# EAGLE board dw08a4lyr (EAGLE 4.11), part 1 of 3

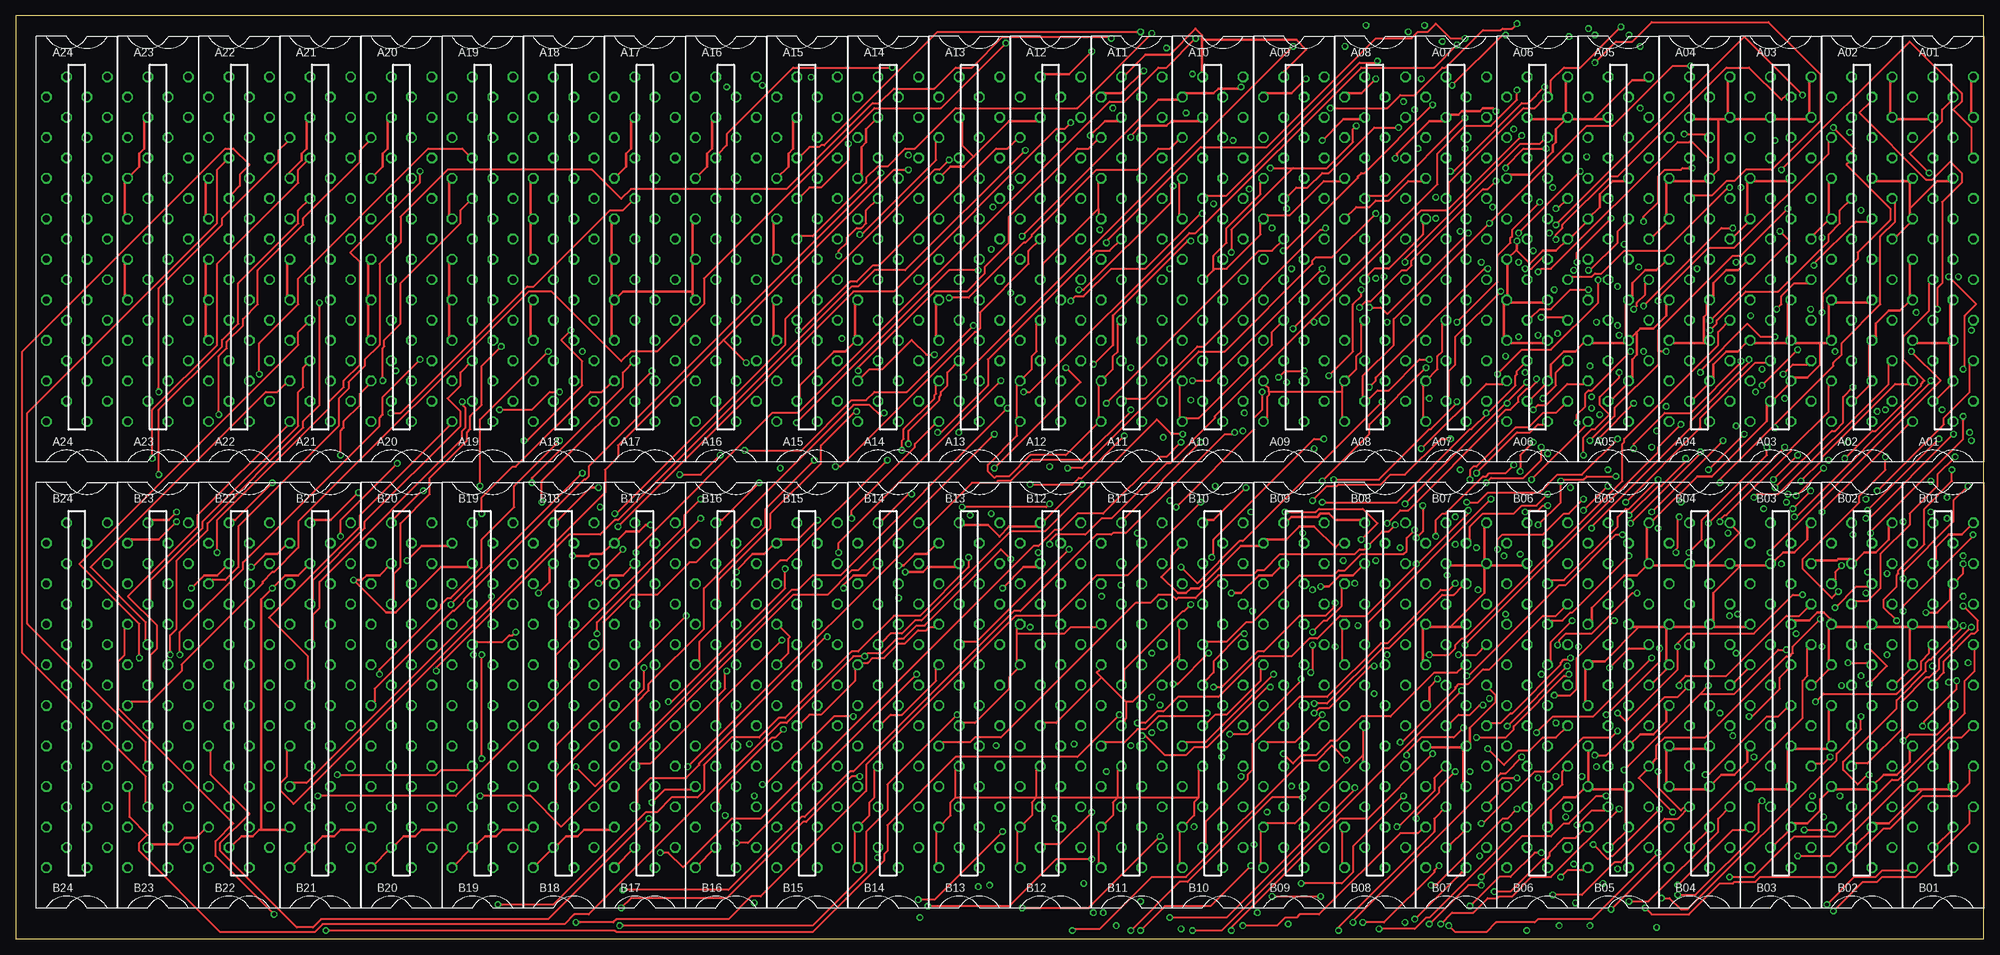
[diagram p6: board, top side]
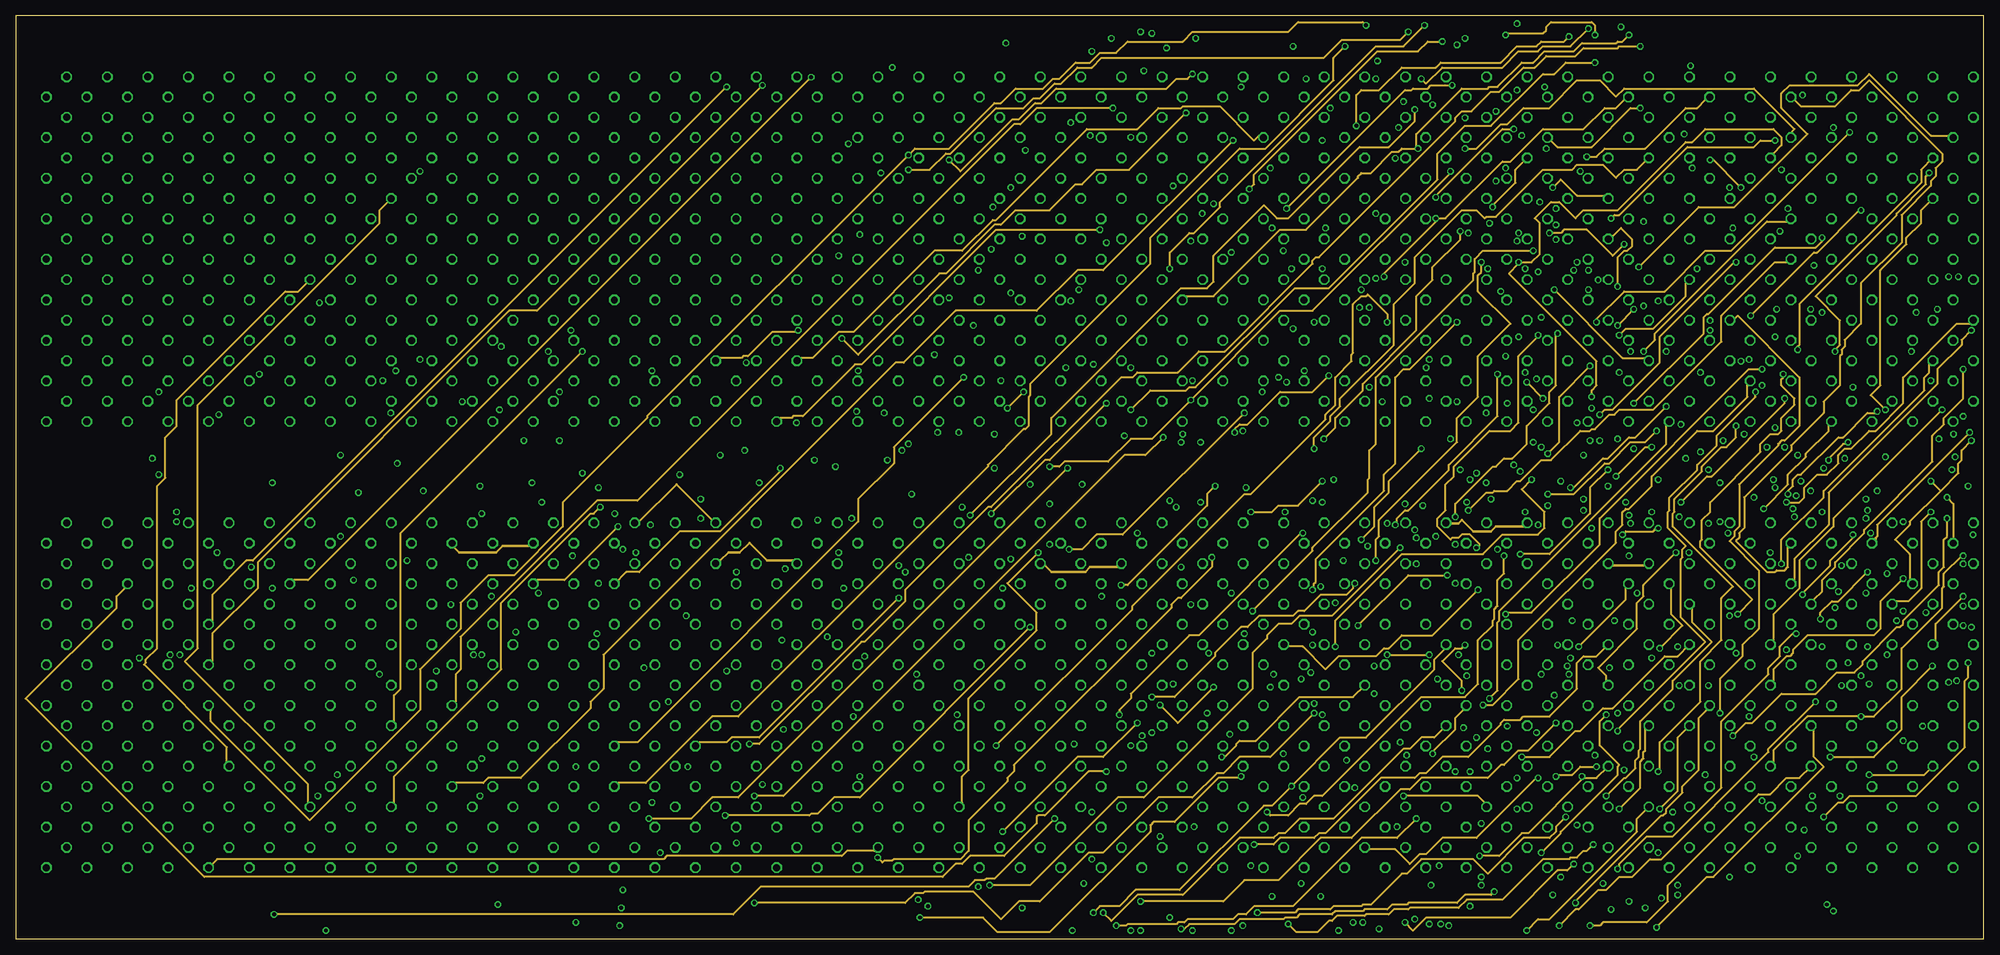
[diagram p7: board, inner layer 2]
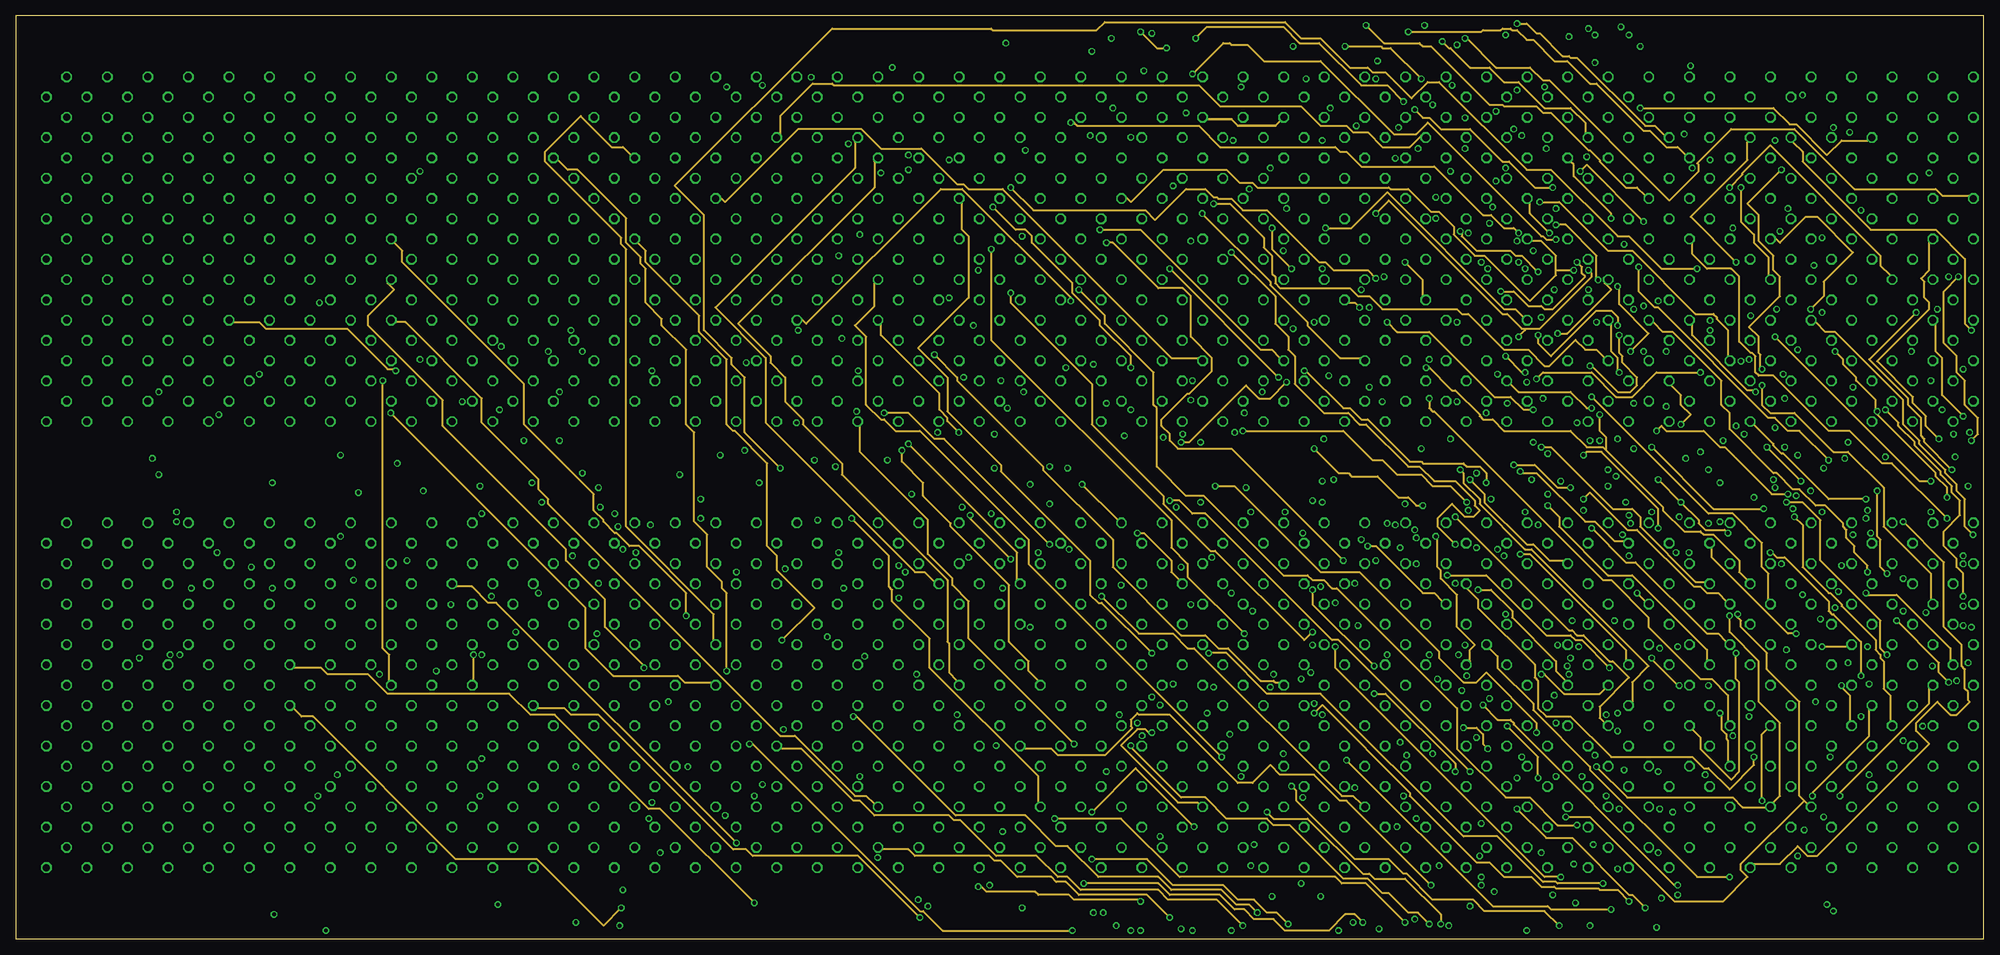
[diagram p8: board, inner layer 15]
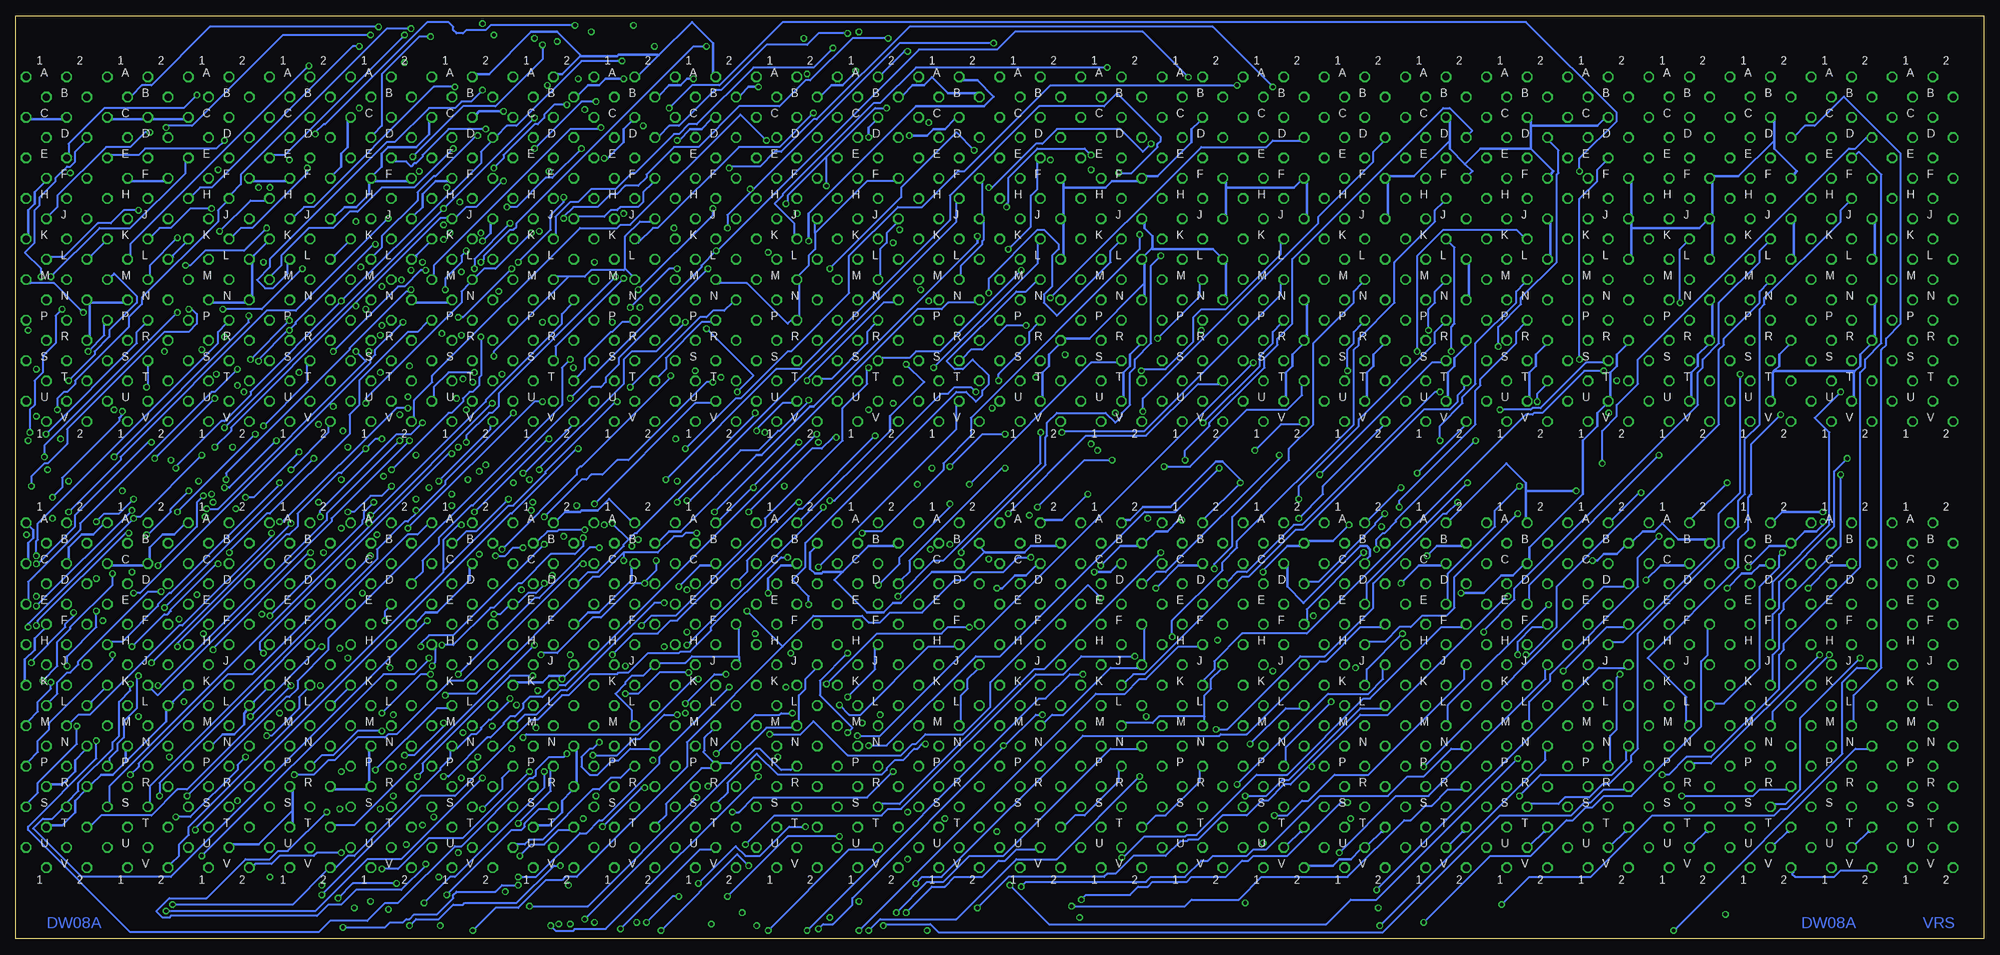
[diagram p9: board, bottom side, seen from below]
Size 307.98 x 144.46 mm. Coordinates in mm from the lower left corner, seen from the top.
Outline: 0,0 307.98,0 307.98,144.46 0,144.46 0,0
Copper layers (1*2*15*16): Top 0.035mm / dielectric 1.5mm / 2 0.035mm / dielectric 0.15mm / 15 0.035mm / dielectric 0.2mm / Bottom 0.035mm
Design rules "10mils": minimum track width 12mil, minimum drill 24mil, track to track 10mil, track to pad 10mil, pad to pad 10mil, via to via 10mil, smd to smd 10mil, copper to edge 25mil, drill to drill 10mil, minimum pad ring 10mil, minimum via ring 8mil, stop-mask expansion 0mil, vias tented up to drill 0mil, thermal gap 10mil
Net classes: 1 supply: width 0.381 mm

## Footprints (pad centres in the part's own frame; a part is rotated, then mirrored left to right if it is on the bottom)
H807 = drill 1.092 octagon: A1 4.763,28.575; A2 -1.587,28.575; B1 1.587,25.4; B2 -4.763,25.4; C1 4.763,22.225; C2 -1.587,22.225; D1 1.587,19.05; D2 -4.763,19.05; E1 4.763,15.875; E2 -1.587,15.875; F1 1.587,12.7; F2 -4.763,12.7; H1 4.763,9.525; H2 -1.587,9.525; J1 1.587,6.35; J2 -4.763,6.35; K1 4.763,3.175; K2 -1.587,3.175; L1 1.587,0; L2 -4.763,0; M1 4.763,-3.175; M2 -1.587,-3.175; N1 1.587,-6.35; N2 -4.763,-6.35; P1 4.763,-9.525; P2 -1.587,-9.525; R1 1.587,-12.7; R2 -4.763,-12.7; S1 4.763,-15.875; S2 -1.587,-15.875; T1 1.587,-19.05; T2 -4.763,-19.05; U1 4.763,-22.225; U2 -1.587,-22.225; V1 1.587,-25.4; V2 -4.763,-25.4

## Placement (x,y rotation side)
A01  M903  [H807]  301.62,106.36 0 top
A02  M903  [H807]  288.93,106.36 0 top
A03  M903  [H807]  276.23,106.36 0 top
A04  M903  [H807]  263.52,106.36 0 top
A05  M903  [H807]  250.82,106.36 0 top
A06  M907  [H807]  238.12,106.36 0 top
A07  M651  [H807]  225.43,106.36 0 top
A08  M651  [H807]  212.72,106.36 0 top
A09  M651  [H807]  200.03,106.36 0 top
A10  M651  [H807]  187.32,106.36 0 top
A11  M651  [H807]  174.62,106.36 0 top
A12  M651  [H807]  161.93,106.36 0 top
A13  W011  [H807]  149.22,106.36 0 top
A14  W011  [H807]  136.53,106.36 0 top
A15  W011  [H807]  123.83,106.36 0 top
A16  W011  [H807]  111.12,106.36 0 top
A17  W011  [H807]  98.42,106.36 0 top
A18  W011  [H807]  85.72,106.36 0 top
A19  W011  [H807]  73.03,106.36 0 top
A20  W011  [H807]  60.33,106.36 0 top
A21  W011  [H807]  47.62,106.36 0 top
A22  W011  [H807]  34.92,106.36 0 top
A23  W011  [H807]  22.23,106.36 0 top
A24  H807  [H807]  9.53,106.36 0 top
B01  M903  [H807]  301.62,36.51 0 top
B02  M903  [H807]  288.93,36.51 0 top
B03  M903  [H807]  276.23,36.51 0 top
B04  M903  [H807]  263.52,36.51 0 top
B05  M903  [H807]  250.82,36.51 0 top
B06  M101  [H807]  238.12,36.51 0 top
B07  M907  [H807]  225.43,36.51 0 top
B08  M651  [H807]  212.72,36.51 0 top
B09  M651  [H807]  200.03,36.51 0 top
B10  M651  [H807]  187.32,36.51 0 top
B11  M651  [H807]  174.62,36.51 0 top
B12  M651  [H807]  161.93,36.51 0 top
B13  M651  [H807]  149.22,36.51 0 top
B14  M651  [H807]  136.53,36.51 0 top
B15  M651  [H807]  123.83,36.51 0 top
B16  M517  [H807]  111.12,36.51 0 top
B17  M517  [H807]  98.42,36.51 0 top
B18  M517  [H807]  85.72,36.51 0 top
B19  M517  [H807]  73.03,36.51 0 top
B20  M517  [H807]  60.33,36.51 0 top
B21  M517  [H807]  47.62,36.51 0 top
B22  M517  [H807]  34.92,36.51 0 top
B23  M517  [H807]  22.23,36.51 0 top
B24  H807  [H807]  9.53,36.51 0 top

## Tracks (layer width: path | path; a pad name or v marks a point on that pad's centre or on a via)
-15V  (via drill 0.61)
  Top 0.381: v87.12,59.94 89.66,59.94 89.92,60.2 91.69,60.2 92.96,61.47 B17.B2 95.5,63.75 97.54,63.75 98.55,64.77 v99.31,64.77 | v25.15,65.28 22.35,62.48 18.03,62.48 B23.B2 | v61.21,59.18 63.5,61.47 67.56,61.47 B19.B2 | v36.83,58.17 37.08,58.17 39.12,60.2 40.89,60.2 42.16,61.47 B21.B2 | v191.77,133.35 191.52,133.1 188.21,133.1 187.45,132.33 183.13,132.33 A10.B2 181.86,131.32 178.82,131.32 v157.48,109.98 | v212.85,134.62 210.57,132.33 208.53,132.33 A08.B2 | v201.93,134.62 199.64,132.33 195.83,132.33 A09.B2 | v176.53,135.89 172.97,132.33 170.43,132.33 A11.B2 | v125.48,65.53 122.43,62.48 119.63,62.48 B15.B2 118.36,61.47 117.09,60.2 115.32,60.2 112.78,57.66 v112.78,57.4 | B08.B2 207.26,61.98 206.5,61.21 203.2,64.52 200.91,64.52 198.88,62.48 195.83,62.48 B09.B2 194.56,61.47 191.77,61.47 185.17,54.86 183.9,54.86 183.13,54.1 181.86,54.1 179.32,56.64 180.85,58.17 180.85,59.94 182.12,61.21 B10.B2 | v138.18,58.42 138.94,58.42 140.72,60.2 142.49,60.2 143.76,61.47 B13.B2
  2 0.381: B18.B2 80.26,61.47 76.2,61.47 75.18,60.45 69.34,60.45 68.58,61.21 B19.B2
  Bottom 0.381: v87.12,59.94 85.6,61.47 81.53,61.47 B18.B2 | v99.31,64.77 101.85,62.23 105.66,62.23 B16.B2 106.93,61.47 108.97,61.47 112.78,57.66 v112.78,57.4 | v25.15,65.28 25.15,64.77 26.16,63.75 27.94,63.75 29.46,62.23 B22.B2 30.73,61.47 33.53,61.47 v36.83,58.17 | B21.B2 43.43,62.48 47.75,62.48 50.29,65.02 51.56,63.75 53.34,63.75 54.86,62.23 B20.B2 56.13,61.47 57.4,60.2 59.44,60.2 60.45,59.18 v61.21,59.18 | A12.B2 157.73,132.33 162.05,132.33 164.59,134.87 165.86,133.6 167.64,133.6 169.16,132.08 A11.B2 | v191.77,133.35 193.29,133.35 194.56,132.08 A09.B2 | v212.85,134.62 215.65,134.62 216.66,133.6 218.44,133.6 219.96,132.08 A07.B2 | v201.93,134.62 202.95,134.62 203.96,133.6 205.74,133.6 207.26,132.08 A08.B2 | v176.53,135.89 176.53,135.64 178.56,133.6 180.34,133.6 181.86,132.08 A10.B2 | v125.48,65.53 125.98,65.53 127.76,63.75 129.54,63.75 131.06,62.23 B14.B2 132.33,61.47 135.13,61.47 v138.18,58.42 | 156.34,60.58 156.97,61.21 B12.B2 | 156.34,60.58 156.21,60.45 150.11,60.45 149.1,61.47 145.03,61.47 B13.B2 | 178.56,57.4 174.5,61.47 170.43,61.47 B11.B2 | 178.56,57.4 181.61,57.4 181.86,57.15 182.88,57.15 183.64,57.91 183.64,60.45 182.88,61.21 B10.B2 | 178.56,57.4 179.83,56.13 174.75,51.05 172.21,51.05 170.69,52.58 169.42,52.58 164.59,57.4 159.51,57.4 156.34,60.58 | v157.48,109.98 157.48,108.97 183.13,83.31 183.64,83.31 191.26,75.69 192.02,75.69 203.96,63.75 205.74,63.75 207.26,62.23 B08.B2
A06U1  (via drill 0.61)
  Top 0.305: v227.58,71.88 227.58,73.41 228.09,73.91 228.6,73.91 234.7,80.01 236.73,80.01 239.01,82.3 241.05,82.3 A06.U1 | A07.J2 220.22,112.01 220.22,110.24 214.88,104.9 212.6,104.9 211.58,103.89 A08.M2 | A07.F2 219.96,118.62 217.93,118.62 214.88,115.57 212.85,115.57 211.84,114.55 209.8,114.55 A08.J2 | 169.42,114.3 169.42,118.36 A11.F2 | 169.42,114.3 169.42,113.28 A11.J2 | 169.42,114.3 160.78,105.66 160.78,103.89 A12.M2 | A10.J2 182.12,113.28 182.12,118.36 A10.F2 | 187.45,104.65 186.44,103.63 A10.M2 | 187.45,104.65 187.71,104.9 189.48,104.9 194.82,110.24 194.82,112.01 A09.J2 195.83,113.28 199.39,113.28 204.72,118.62 207.26,118.62 A08.F2 | 187.45,104.65 187.45,106.93 189.48,108.97 189.48,111.25 194.82,116.59 194.82,118.36 A09.F2
  15 0.305: v227.58,71.88 229.87,69.6 229.87,68.33 236.47,61.72 237.49,61.72 240.03,59.18 242.32,59.18 B06.C1 | v236.22,88.65 235.71,88.65 v233.17,91.19
  Bottom 0.305: 212.6,104.9 212.6,109.98 210.31,112.27 208.53,112.27 A08.J2 | 212.6,104.9 211.58,103.89 A08.M2 | 221.49,103.63 218.95,103.63 217.93,104.65 212.85,104.65 212.6,104.9 | 221.49,103.63 223.27,103.63 A07.M2 | A12.F2 156.72,118.36 156.72,113.28 A12.J2 156.46,112.27 156.46,109.47 156.72,109.22 156.72,108.71 160.02,105.41 160.02,103.89 A12.M2 | A11.M2 172.72,103.89 172.72,107.95 171.7,108.97 171.7,110.49 170.18,112.01 A11.J2 | A09.M2 197.87,102.62 193.55,102.62 187.2,96.27 186.44,97.03 A10.P2 185.42,97.54 185.42,102.62 A10.M2 185.42,103.89 183.9,105.41 183.9,106.93 182.88,107.95 182.88,110.49 | 182.88,110.49 182.88,112.01 A10.J2 | 182.88,110.49 174.75,118.62 170.43,118.62 A11.F2 | A07.J2 219.96,113.03 215.9,113.03 214.88,114.05 213.87,114.05 213.36,114.55 210.57,114.55 209.8,115.32 209.8,116.84 208.28,118.36 A08.F2 | v236.22,88.65 240.28,88.65 242.57,86.36 242.57,84.84 A06.U1 | v233.17,91.19 233.17,91.95 221.49,103.63
A06V1  (via drill 0.61)
  Top 0.305: A12.P2 159.77,96.27 159.77,91.95 159,91.19 159,89.15 A12.T2 156.72,86.61 156.72,81.53 A12.V2 156.72,80.26 156.72,78.74 152.15,74.17 152.15,73.15 153.16,72.14 153.42,72.39 155.45,72.39 158.75,75.69 164.34,75.69 169.16,80.52 A11.V2 169.42,81.53 169.42,86.61 A11.T2 171.7,89.15 171.7,91.19 172.47,91.95 172.47,96.27 A11.P2 | A10.T2 182.12,86.61 182.12,81.53 A10.V2 183.13,81.53 185.17,81.53 196.6,92.96 196.6,95 A09.P2 | 196.09,85.6 196.09,86.11 195.58,86.61 A09.T2 | 196.09,85.6 196.09,85.09 195.83,84.84 195.83,81.53 A09.V2 | 207.52,85.6 207.52,86.61 A08.T2 209.8,89.15 209.8,91.19 210.57,91.95 210.57,96.27 A08.P2 | 207.52,85.6 207.52,81.53 A08.V2 | 207.52,85.6 196.09,85.6 | A07.V2 220.22,81.53 220.22,86.61 A07.T2 222.5,89.15 222.5,91.19 223.27,91.95 223.27,96.27 A07.P2 | v228.6,72.9 234.95,79.25 236.98,79.25 238.25,80.52 239.01,80.52 A06.V1
  Bottom 0.305: A10.T2 181.86,87.63 180.34,87.63 174.75,93.22 174.75,95 173.48,96.27 A11.P2 | A09.P2 199.14,96.52 200.66,96.52 206.25,90.93 206.25,89.15 207.52,87.88 A08.T2 | v228.6,72.9 228.35,72.9 220.98,80.26 A07.V2 | A08.P2 211.84,96.52 213.11,96.52 214.63,95 214.88,95 218.95,90.93 218.95,89.15 220.22,87.88 A07.T2
B07U1
  Top 0.305: B09.V2 194.82,11.68 194.82,16.76 B09.T2 195.83,18.03 200.15,18.03 210.82,28.7 | 210.82,28.7 210.82,32.77 B08.M2 | 210.82,28.7 210.82,27.69 B08.P2 | B13.F2 143.76,48.77 143,48.77 142.49,48.26 141.22,48.26 139.19,46.23 138.18,46.23 135.89,43.94 134.11,43.94 133.35,43.18 132.33,43.18 B14.J2 131.32,42.16 131.32,40.39 125.98,35.05 124.21,35.05 122.94,33.78 B15.M2 | B13.J2 144.02,42.16 144.02,40.39 138.68,35.05 136.91,35.05 135.64,33.78 B14.M2 | B15.F2 119.63,48.77 121.16,47.24 120.9,46.99 120.9,44.7 B15.J2 | B13.M2 148.34,33.78 150.11,33.78 155.45,39.12 155.45,40.89 156.72,42.16 B12.J2 156.72,43.43 156.72,47.75 | 156.72,47.75 156.72,48.51 B12.F2 | 156.72,47.75 164.08,47.75 165.1,48.77 169.16,48.77 B11.F2 | B08.V2 207.52,11.68 207.52,16.76 B08.T2 | 173.74,37.08 173.74,34.54 173.48,34.29 173.48,34.04 B11.M2 | 169.93,40.89 169.16,41.66 169.67,42.16 B11.J2 | 173.74,37.08 169.93,40.89 | B08.J2 207.52,43.43 207.52,48.51 B08.F2 | 182.12,44.45 182.12,43.43 B10.J2 | 182.12,44.45 182.12,48.51 B10.F2 | B09.J2 194.82,42.16 194.82,40.39 189.48,35.05 187.71,35.05 186.44,33.78 B10.M2 | 173.74,37.08 174.75,37.08 182.12,44.45 | 169.93,40.89 162.81,33.78 161.04,33.78 B12.M2
  Bottom 0.305: B07.U1 229.62,14.73 228.35,14.73 227.58,15.49 225.55,15.49 217.68,23.37 216.66,23.37 214.88,25.15 213.36,25.15 211.84,26.67 B08.P2 | B14.F2 131.32,48.51 131.32,43.43 B14.J2 132.33,42.42 136.65,42.42 144.02,35.05 145.8,35.05 147.07,33.78 B13.M2 | 121.92,34.8 121.92,38.1 120.9,39.12 120.9,40.64 119.38,42.16 B15.J2 | 121.92,34.8 121.92,34.04 B15.M2 | 121.92,34.8 129.03,34.8 130.05,33.78 134.37,33.78 B14.M2 | B12.M2 160.02,34.04 160.02,38.1 159,39.12 159,40.64 157.48,42.16 B12.J2 | B09.P2 198.88,27.69 200.41,29.21 200.15,29.46 200.15,31.5 198.88,32.77 B09.M2 | B09.P2 199.14,26.67 200.66,26.67 206.25,21.08 206.25,19.3 207.52,18.03 B08.T2 | 194.82,44.2 194.82,48.51 B09.F2 | 194.82,44.2 194.82,43.43 B09.J2 | B10.J2 182.88,42.16 184.4,40.64 184.4,39.12 185.42,38.1 185.42,34.04 B10.M2 186.44,33.02 190.5,33.02 196.09,27.43 197.87,27.43 B09.P2 | 194.82,44.2 202.18,44.2 203.2,43.18 207.26,43.18 B08.J2 208.53,42.42 209.8,41.15 211.58,41.15 212.6,40.13 212.6,39.88 214.12,38.35 211.58,35.81 211.58,34.04 B08.M2
B07V1  (via drill 0.61)
  Top 0.305: B14.V2 131.32,11.68 131.32,16.76 B14.T2 133.6,19.3 133.6,21.34 134.37,22.1 134.37,26.42 B14.P2 | B13.V2 144.02,11.68 144.02,16.76 B13.T2 146.3,19.3 146.3,21.34 147.07,22.1 | 147.07,22.1 147.07,26.42 B13.P2 | B12.V2 156.72,11.68 156.72,16.76 B12.T2 159,19.3 159,21.34 159.77,22.1 | 159.77,22.1 159.77,26.42 B12.P2 | 147.07,22.1 159.77,22.1 | B11.V2 169.42,11.68 169.42,16.76 B11.T2 171.7,19.3 171.7,21.34 172.47,22.1 | 172.47,22.1 172.47,26.42 B11.P2 | B10.V2 182.12,11.68 182.12,16.76 B10.T2 184.4,19.3 184.4,21.34 185.17,22.1 | 185.17,22.1 185.17,26.42 B10.P2 | v218.95,3.05 226.31,10.41 226.57,10.41 B07.V1 | 172.47,22.1 185.17,22.1 | 159.77,22.1 172.47,22.1
  Bottom 0.305: B15.P2 122.68,26.42 122.68,24.64 128.02,19.3 129.54,19.3 131.06,17.78 B14.T2 | B14.P2 135.38,26.42 135.38,24.64 140.72,19.3 142.24,19.3 143.76,17.78 B13.T2 | v218.95,3.05 192.28,29.72 191.52,29.72 188.21,26.42 186.69,26.42 186.44,26.67 B10.P2
GND  (via drill 0.61)
  Top 0.381: 264.16,93.22 264.41,93.22 A04.R1 | 264.16,93.22 259.33,93.22 A04.R2 | 264.16,93.22 264.16,97.28 264.67,97.79 264.67,99.31 A04.N1 265.68,100.58 265.68,102.62 267.72,104.65 269.49,104.65 270.76,105.92 A03.L2 | A04.K1 268.99,109.98 271.02,112.01 A03.J2 271.02,113.28 271.02,118.36 A03.F2 272.03,118.62 277.11,118.62 A03.F1 | A03.K1 281.43,110.24 283.46,112.27 A02.J2 283.72,113.28 283.72,118.36 A02.F2 | A02.K1 294.39,109.98 296.42,112.01 A01.J2 296.42,113.28 296.42,114.3 | 296.42,114.3 296.42,118.36 A01.F2 296.16,118.62 291.08,118.62 A02.F1 | 296.42,114.3 300.74,118.62 302.51,118.62 A01.F1 | A02.U2 288.04,84.58 290.07,86.61 A02.T1 290.07,87.88 290.07,92.96 A02.R1 291.08,94.23 291.08,96.27 293.12,98.3 294.89,98.3 296.16,99.57 A01.N2 296.42,100.58 296.42,105.66 A01.L2 | A01.U2 300.74,84.58 302.77,86.61 A01.T1 302.77,87.88 302.77,92.96 A01.R1 | A01.R2 297.43,93.22 302.51,93.22 A01.R1 | A01.N1 302.77,99.31 302.77,94.23 A01.R1 | A04.U2 262.64,84.58 264.67,86.61 A04.T1 265.68,87.88 265.68,89.92 267.72,91.95 269.49,91.95 270.76,93.22 A03.R2 272.03,93.22 277.11,93.22 A03.R1 | 282.45,93.22 278.38,93.22 A03.R1 | 282.45,93.22 283.46,93.22 A02.R2 283.72,94.23 283.72,99.31 A02.N2 284.73,99.57 289.81,99.57 A02.N1 | 282.45,93.22 282.45,89.92 280.42,87.88 278.38,87.88 A03.T1 277.37,86.61 275.34,84.58 A03.U2 274.07,83.57 274.07,81.03 265.43,72.39 263.14,72.39 256.29,65.53 B05.A1 255.27,64.52 255.27,59.44 B05.C1 | A03.N1 277.37,99.31 277.37,94.23 A03.R1 | 266.45,128.27 267.72,128.27 A04.C1 | 266.45,128.27 262.64,128.27 A04.C2 | A04.C1 268.99,128.27 274.07,128.27 A03.C2 275.34,128.27 280.42,128.27 A03.C1 280.67,129.29 280.67,134.37 A03.A1
  Top 0.381: A04.A1 267.97,134.37 267.97,129.29 A04.C1 | A01.C2 299.47,128.27 294.39,128.27 A02.C1 293.37,129.29 293.37,134.37 A02.A1 | A01.A1 306.07,134.37 306.07,129.29 A01.C1 | v231.65,129.54 231.14,130.05 229.62,130.05 229.11,129.54 226.31,129.54 225.81,129.03 224.54,129.03 A07.C2 223.27,128.02 221.23,128.02 216.15,122.94 216.15,122.43 v215.9,122.17 | A06.F2 233.93,119.63 236.98,119.63 240.54,123.19 240.54,124.21 241.05,124.71 241.05,126.75 A06.C1 | 246.89,128.27 243.59,128.27 A06.C1 | 246.89,128.27 248.67,128.27 A05.C2 | A06.A1 242.57,134.37 242.57,129.29 A06.C1 | 246.89,128.27 252.98,134.37 255.02,134.37 A05.A1 | A06.C2 237.24,128.27 242.32,128.27 A06.C1 | A05.U2 249.94,84.58 251.97,86.61 A05.T1 252.98,87.88 252.98,90.68 253.75,91.44 253.75,94.74 253.62,94.87 | A06.U2 237.24,84.58 239.27,86.61 A06.T1 240.28,87.88 240.28,89.92 242.32,91.95 244.09,91.95 245.36,93.22 A05.R2 246.63,93.22 251.71,93.22 A05.R1 | A05.R1 251.97,94.23 251.97,99.31 A05.N1 252.98,100.58 252.98,102.62 255.02,104.65 256.79,104.65 258.06,105.92 A04.L2 | 253.62,94.87 254.25,95.5 256.29,95.5 258.32,97.54 258.32,99.31 A04.N2 | A05.R1 253.62,94.87 | A06.R1 239.01,93.22 233.93,93.22 A06.R2 232.92,94.23 232.92,99.31 A06.N2 | A06.N1 239.01,99.57 233.93,99.57 A06.N2 | A06.N2 233.43,100.58 233.43,105.66 A06.L2 234.82,107.82 | v234.95,109.22 234.95,107.95 234.82,107.82 | A05.F1 251.71,118.62 249.94,118.62 247.9,116.59 247.9,114.55 A05.J2 245.62,112.01 243.59,109.98 A06.K1 241.05,107.7 239.01,107.7 236.98,105.66 234.82,107.82 | A05.K1 256.29,109.98 258.32,112.01 A04.J2 258.32,113.28 258.32,118.36 A04.F2 259.33,118.62 264.41,118.62 A04.F1 266.45,120.4 266.45,128.27
  Top 0.381: B07.U2 224.54,14.73 226.57,16.76 B07.T1 | B07.R1 226.57,24.38 226.57,29.46 B07.N1 | B07.N2 221.23,29.97 226.31,29.97 B07.N1 | B07.C2 224.54,58.42 229.62,58.42 B07.C1 | B06.C2 235.97,58.42 230.89,58.42 B07.C1 | B07.A1 229.87,64.52 229.87,59.44 B07.C1 | v222.5,40.64 221.23,39.37 221.23,37.08 B07.L2 | v190.25,54.1 191.77,54.1 194.56,56.9 196.6,56.9 B09.C2 | 224.54,48.77 221.23,48.77 B07.F2 220.22,48.51 220.22,43.43 B07.J2 | 224.54,48.77 226.31,48.77 B07.F1 | v204.22,55.12 205.49,55.12 207.26,56.9 209.3,56.9 B08.C2 | 224.54,48.77 229.87,54.1 229.87,58.17 B07.C1 | B07.N1 227.58,30.73 227.58,33.02 231.65,37.08 231.65,38.1 230.63,39.12 B07.K1 | B05.K1 256.29,40.13 258.32,42.16 B04.J2 258.32,43.43 258.32,48.51 B04.F2 | B05.L2 245.62,37.08 245.62,42.16 B05.J2 246.63,43.43 248.67,43.43 254,48.77 | 254,48.77 258.06,48.77 B04.F2 | 254,48.77 252.98,48.77 B05.F1 | B04.F1 264.41,48.77 259.33,48.77 B04.F2 | B03.F2 270.76,48.77 265.68,48.77 B04.F1 | B01.C2 300.48,59.44 300.48,61.21 302.51,63.25 304.55,63.25 B01.A1 | B03.C1 281.69,59.18 284.99,59.18 285.24,59.44 287.02,59.44 B02.C2 288.04,59.18 289.31,60.45 291.08,60.45 293.12,62.48 293.12,64.52 B02.A1 | B05.F2 246.63,49.78 246.63,51.82 251.71,56.9 253.75,56.9 B05.C1 | B05.C1 256.29,58.42 261.37,58.42 B04.C2 262.64,58.42 264.67,58.42 | 264.67,58.42 267.72,58.42 B04.C1 268.99,58.42 270,58.42 | 270,58.42 274.07,58.42 B03.C2 275.34,59.18 276.61,60.45 278.38,60.45 280.42,62.48 280.42,64.52 B03.A1 | 264.67,58.42 269.75,63.5 268.73,64.52 B04.A1 | 270,58.42 265.68,54.1 265.68,49.78 B04.F1 | B03.K1 281.69,40.13 283.72,42.16 B02.J2 283.72,43.43 283.72,48.51 B02.F2
  Top 0.381: B04.K1 268.99,40.13 271.02,42.16 B03.J2 | B03.R2 272.03,23.37 277.11,23.37 B03.R1 277.37,24.38 277.37,29.46 B03.N1 278.38,29.72 283.46,29.72 B02.N2 283.72,30.73 283.72,35.81 B02.L2 | B03.F1 278.38,49.78 280.67,49.78 281.94,51.05 282.96,51.05 283.97,50.04 283.72,49.78 B02.F2 | B02.F2 284.73,48.77 289.81,48.77 B02.F1 291.08,48.77 296.16,48.77 B01.F2 | B02.K1 294.39,40.13 296.42,42.16 B01.J2 296.42,43.43 296.42,48.51 B01.F2 | B01.F1 302.51,48.77 297.43,48.77 B01.F2 | B01.U2 300.74,14.73 302.77,16.76 B01.T1 | B02.U2 288.04,14.73 290.07,16.76 B02.T1 291.08,18.03 293.12,18.03 298.45,23.37 | 298.45,23.37 297.43,23.37 B01.R2 | 298.45,23.37 302.51,23.37 B01.R1 302.77,24.38 302.77,29.46 B01.N1 | B03.U2 275.34,14.73 277.37,16.76 B03.T1 278.38,18.03 280.42,18.03 282.45,20.07 282.45,21.84 283.72,23.11 B02.R2 284.73,23.37 289.81,23.37 B02.R1 292.35,25.65 294.39,25.65 296.42,27.69 296.42,29.46 B01.N2 | B04.U2 262.64,14.73 264.67,16.76 B04.T1 | B03.N2 271.02,29.46 271.02,27.69 268.99,25.65 266.95,25.65 B04.R1 264.41,23.37 259.33,23.37 B04.R2 258.32,24.38 258.32,29.46 B04.N2 259.33,29.72 264.41,29.72 B04.N1 | B06.T1 240.28,18.03 240.28,20.07 242.32,22.1 244.09,22.1 245.36,23.37 B05.R2 | B05.N2 246.13,29.46 246.13,24.38 B05.R2 | B05.U2 249.94,14.73 251.97,16.76 B05.T1 251.97,18.03 251.97,23.11 B05.R1 251.71,23.37 246.63,23.37 B05.R2 | B04.L2 258.32,35.81 258.32,34.04 256.29,32 254.25,32 B05.N1 | B16.V2 B16.U2 | B17.U2 B17.V2 | B18.V2 B18.U2 84.84,14.73 86.11,16 87.88,16 88.9,17.02 92.96,17.02 B17.T2 | B19.V2 B19.U2 72.14,14.73 73.41,16 75.18,16 76.2,17.02 80.26,17.02 B18.T2
  Top 0.381: B20.V2 B20.U2 59.44,14.73 60.71,16 62.48,16 63.5,17.02 67.56,17.02 B19.T2 | B21.V2 B21.U2 46.74,14.73 48.01,16 49.78,16 50.8,17.02 54.86,17.02 B20.T2 | B23.U2 21.34,14.73 25.4,14.73 26.42,15.75 28.19,15.75 29.46,17.02 B22.T2 | 38.35,17.02 38.1,17.02 37.08,16 35.31,16 34.04,14.73 B22.U2 | 38.35,17.02 42.16,17.02 B21.T2 | v129.54,54.86 129.54,55.37 131.06,56.9 133.1,56.9 B14.C2 | v139.19,57.4 141.99,57.4 142.75,58.17 147.07,58.17 B13.C2 | v154.43,54.86 157.73,58.17 159.77,58.17 B12.C2 | v91.19,55.63 91.69,55.63 92.96,56.9 95,56.9 B17.C2 | v27.43,54.86 29.46,56.9 31.5,56.9 B22.C2 | B20.C2 56.9,56.9 54.86,56.9 54.1,56.13 v52.83,56.13 57.91,51.05 59.44,51.05 66.55,58.17 70.87,58.17 B19.C2 | B21.C2 44.2,56.9 42.16,56.9 v40.13,54.86 38.35,53.09 38.35,17.02 | v81.79,54.1 83.57,55.88 83.57,58.17 B18.C2 | v204.47,124.97 207.77,128.27 210.57,128.27 A08.C2 | A14.F2 132.33,119.63 132.33,123.95 133.1,124.71 133.1,126.75 A14.C2 | 149.86,122.43 148.08,124.21 148.08,128.02 A13.C2 | 149.86,122.43 148.34,120.9 146.3,120.9 A13.F2 | 149.86,122.43 155.45,128.02 159.77,128.02 A12.C2 | v168.15,125.73 170.43,128.02 172.47,128.02 A11.C2 | v174.5,125.48 174.5,125.73 176.02,127.25 180.09,127.25 180.85,128.02 185.17,128.02 A10.C2 | A13.R2 144.02,94.23 144.02,99.31 A13.N2 | A15.U2 122.68,84.84 122.68,86.61 128.02,91.95 129.79,91.95 131.06,93.22 A14.R2 131.32,94.23 131.32,99.31 A14.N2 | A15.R2 118.62,94.23 118.62,99.31 A15.N2 | A15.J2 118.62,112.01 118.62,106.93 A15.L2 | A15.C2 121.67,128.02 121.67,123.7 120.9,122.94 120.9,120.9 A15.F2 | 105.92,101.35 105.92,100.58 A16.N2 | 105.92,101.35 105.92,105.66 A16.L2 105.92,106.93 105.92,112.01 A16.J2
  Top 0.381: A16.C2 108.97,128.02 108.97,123.7 108.2,122.94 108.2,120.9 A16.F2 | A17.R2 93.22,94.23 93.22,99.31 A17.N2 | A17.N2 93.22,100.58 93.22,105.66 A17.L2 93.22,106.93 93.22,112.01 A17.J2 | A17.C2 96.27,128.02 96.27,123.7 95.5,122.94 95.5,120.9 A17.F2 | A19.R2 67.82,94.23 67.82,99.31 A19.N2 67.82,100.58 67.82,105.66 A19.L2 | A19.F2 67.82,118.36 67.82,113.28 A19.J2 | A18.R2 80.52,94.23 80.52,99.31 A18.N2 | A18.L2 80.52,106.93 80.52,112.01 A18.J2 80.52,113.28 80.52,118.36 A18.F2 | A20.R2 55.12,94.23 55.12,99.31 A20.N2 55.12,100.58 55.12,105.66 A20.L2 | A20.C2 58.17,128.02 58.17,123.7 57.4,122.94 57.4,120.9 A20.F2 | A21.L2 42.42,105.66 42.42,100.58 A21.N2 | A21.C2 45.47,128.02 45.47,123.7 44.7,122.94 44.7,121.92 42.42,119.63 A21.F2 | A23.L2 17.02,105.66 17.02,100.58 A23.N2 | A23.J2 17.02,113.28 17.02,118.36 A23.F2 19.3,120.9 19.3,122.94 20.07,123.7 20.07,128.02 A23.C2 | A22.R2 29.72,94.23 29.72,99.31 A22.N2 29.72,100.58 29.72,105.66 A22.L2 | A22.F2 29.72,118.36 29.72,113.28 A22.J2 | 105.92,101.35 95,101.35 A17.N2
  2 0.381: B05.C2 249.94,58.42 255.02,58.42 B05.C1 | B11.C2 172.47,58.17 168.15,58.17 167.39,57.4 162.05,57.4 161.04,58.42 B12.C2 | B15.C2 121.67,59.18 117.6,59.18 114.81,61.98 113.28,60.45 111.51,60.45 110.24,59.18 B16.C2
  15 0.381: A10.C2 186.44,128.27 190.25,128.27 191.26,127.25 197.1,127.25 A09.C2
  Bottom 0.381: A03.N1 277.11,99.57 272.03,99.57 A03.N2 271.02,100.58 271.02,105.66 A03.L2 270.76,106.68 270.76,106.93 268.73,108.97 A04.K1 | A02.L2 283.46,106.68 283.46,106.93 281.43,108.97 A03.K1 | A02.F1 289.81,118.62 284.73,118.62 A02.F2 | A01.L2 296.16,106.68 296.16,106.93 294.13,108.97 A02.K1 | A01.K1 306.07,110.24 306.07,114.05 305.05,115.06 305.05,116.84 303.53,118.36 A01.F1 | A01.R2 296.42,94.23 296.42,99.31 A01.N2 296.16,99.57 291.08,99.57 A02.N1 | A03.C1 281.69,128.27 286.77,128.27 A02.C2 288.04,128.27 293.12,128.27 A02.C1 | A01.C1 305.82,128.27 300.74,128.27 A01.C2 | v231.65,129.54 235.46,129.54 235.97,129.03 A06.C2 | A05.N2 245.36,99.57 240.28,99.57 A06.N1 | v234.95,109.22 233.68,110.49 233.68,112.01 A06.J2 | A05.F2 246.63,118.62 251.71,118.62 A05.F1 | A05.L2 245.36,106.68 245.36,106.93 243.33,108.97 A06.K1 | A06.F1 240.28,118.62 242.32,118.62 244.35,116.59 244.35,114.55 245.62,113.28 A05.J2 | A04.L2 258.06,106.68 258.06,106.93 256.03,108.97 A05.K1 | A05.C1 256.03,128.02 256.03,123.95 257.05,122.94 257.05,120.9 258.32,119.63 A04.F2 | A05.F1 252.73,118.36 252.73,116.59 254.76,114.55 256.54,114.55 258.06,113.03 A04.J2 | A06.C1 243.33,128.02 243.33,125.98 245.36,123.95 249.68,123.95 250.7,122.94 250.7,120.9 251.97,119.63 A05.F1 | A03.F2 270.76,118.62 265.68,118.62 A04.F1 | B07.N2 220.22,29.46 220.22,24.38 B07.R2 220.98,23.11 222.5,21.59 222.5,19.81 224.54,17.78 226.31,17.78 B07.T1 | 222.12,41.02 220.98,42.16 B07.J2 | 222.12,41.02 v222.5,40.64 | B07.K1 229.62,40.13 225.55,40.13 224.54,41.15 222.25,41.15 222.12,41.02 | v190.25,54.1 190.25,56.39 188.21,58.42 186.44,58.42 B10.C2
  Bottom 0.381: B08.C2 211.58,58.17 211.58,56.13 216.66,51.05 218.44,51.05 219.96,49.53 B07.F2 | v204.22,55.12 200.91,58.42 199.14,58.42 B09.C2 | B04.L2 258.06,36.83 258.06,37.08 256.03,39.12 B05.K1 | B01.C1 306.07,59.44 306.07,61.98 305.31,62.74 305.31,64.01 B01.A1 | B02.C1 293.12,58.42 288.04,58.42 B02.C2 287.02,59.44 287.02,61.21 284.99,63.25 283.21,63.25 281.69,64.77 B03.A1 | B01.C2 299.72,59.44 299.72,61.21 297.69,63.25 295.91,63.25 294.39,64.77 B02.A1 | B03.K1 281.43,39.12 283.46,37.08 283.46,36.83 B02.L2 284.48,35.81 284.48,34.04 290.83,27.69 | B04.K1 268.73,39.12 270.76,37.08 270.76,36.83 B03.L2 271.78,35.81 272.29,35.31 272.29,33.53 273.81,32 275.59,32 277.11,30.48 B03.N1 | B01.L2 296.16,36.83 296.16,37.08 294.13,39.12 B02.K1 | B01.K1 306.58,40.39 306.58,43.69 305.05,45.21 305.05,46.99 303.53,48.51 B01.F1 | 290.83,27.69 290.83,29.46 B02.N1 | 290.83,27.69 292.86,25.65 294.64,25.65 296.16,24.13 B01.R2 297.18,23.11 298.7,21.59 298.7,19.81 300.74,17.78 302.51,17.78 B01.T1 | B01.R1 302.51,24.13 300.74,24.13 298.7,26.16 298.7,27.94 297.18,29.46 B01.N2 | 264.67,20.07 264.67,18.03 B04.T1 | 264.67,20.07 264.67,23.11 B04.R1 | B05.N1 252.73,29.46 252.73,24.38 B05.R1 252.98,23.37 258.06,23.37 B04.R2 | 264.67,20.07 270,14.73 274.07,14.73 B03.U2 | B06.C2 236.98,58.17 236.98,56.13 242.06,51.05 243.84,51.05 245.36,49.53 B05.F2 | B16.T2 106.68,16.76 106.93,16.76 108.97,14.73 B16.U2 | B17.T2 93.98,16.76 94.23,16.76 96.27,14.73 B17.U2 97.54,13.97 99.06,12.45 100.84,12.45 101.85,11.43 105.66,11.43 B16.V2 | B18.T2 81.28,16.76 81.53,16.76 83.57,14.73 B18.U2 | B19.T2 68.58,16.76 68.83,16.76 70.87,14.73 B19.U2
  Bottom 0.381: B20.T2 55.88,16.76 56.13,16.76 58.17,14.73 B20.U2 | B21.T2 43.18,16.76 43.43,16.76 45.47,14.73 B21.U2 | B23.T2 17.78,16.76 18.03,16.76 20.07,14.73 B23.U2 | B22.T2 30.48,16.76 30.73,16.76 32.77,14.73 B22.U2 | v129.54,54.86 125.98,58.42 122.94,58.42 B15.C2 | v139.19,57.4 136.65,57.4 135.64,58.42 B14.C2 | v154.43,54.86 153.67,54.86 151.64,56.9 149.86,56.9 148.34,58.42 B13.C2 | v91.19,55.63 88.39,58.42 84.84,58.42 B18.C2 | B16.C2 108.97,58.17 108.97,55.12 106.43,52.58 97.54,61.47 96.52,61.47 96.01,60.96 96.01,59.94 96.52,59.44 B17.C2 | v27.43,54.86 23.88,58.42 21.34,58.42 B23.C2 | v52.83,56.13 50.55,58.42 46.74,58.42 B21.C2 | v40.13,54.86 37.85,57.15 36.32,57.15 35.05,58.42 34.04,58.42 B22.C2 | v81.79,54.1 78.23,54.1 75.44,56.9 73.66,56.9 72.14,58.42 B19.C2 71.12,59.44 71.12,61.21 62.74,69.6 62.74,77.98 60.45,80.26 60.45,82.3 59.18,83.57 A20.U2 58.42,84.84 58.42,88.65 57.4,89.66 57.4,91.44 55.88,92.96 A20.R2 | v204.47,124.97 204.22,124.97 202.44,126.75 200.66,126.75 199.14,128.27 A09.C2 | A13.L2 144.02,106.93 144.02,112.01 A13.J2 144.02,113.28 144.02,117.6 | 144.02,117.6 144.02,118.36 A13.F2 | v168.15,125.73 165.35,125.73 164.34,126.75 162.56,126.75 161.04,128.27 A12.C2 | 144.02,117.6 137.41,117.6 136.4,118.62 132.33,118.62 A14.F2 131.06,119.38 129.29,119.38 123.95,124.71 123.95,126.75 122.68,128.02 A15.C2 | v174.5,125.48 174.5,127 173.48,128.02 A11.C2 | A13.U2 147.32,84.84 147.32,88.65 146.3,89.66 146.3,91.44 144.78,92.96 A13.R2 143.76,93.98 139.95,93.98 131.32,102.62 | 131.32,102.62 131.32,100.58 A14.N2 | 131.32,102.62 131.32,105.66 A14.L2 131.32,106.93 130.18,108.08
  Bottom 0.381: A14.U2 134.62,84.84 134.62,88.65 133.6,89.66 133.6,91.44 132.08,92.96 A14.R2 | 130.18,108.08 130.05,108.2 130.05,109.98 131.32,111.25 131.32,112.01 A14.J2 | A15.N2 118.62,100.58 118.62,105.66 A15.L2 120.65,107.95 130.05,107.95 130.18,108.08 | 118.62,117.6 118.62,113.28 A15.J2 | 118.62,117.6 118.62,118.36 A15.F2 | A16.N2 105.92,99.31 105.92,94.23 A16.R2 106.68,92.96 108.2,91.44 108.2,89.66 109.22,88.65 109.22,84.84 A16.U2 | A16.J2 105.92,113.28 105.92,118.36 A16.F2 106.93,118.62 107.95,117.6 118.62,117.6 | A17.U2 96.52,84.84 96.52,88.65 95.5,89.66 95.5,91.44 93.98,92.96 A17.R2 | A17.J2 93.22,113.28 93.22,118.36 A17.F2 92.96,119.38 89.15,119.38 83.57,124.97 | A19.U2 71.12,84.84 71.12,88.65 70.1,89.66 70.1,91.44 68.58,92.96 A19.R2 | A19.J2 67.82,112.01 67.82,106.93 A19.L2 | 70.87,123.7 70.87,127.25 | 70.87,127.25 70.87,128.02 A19.C2 | 70.87,123.7 67.31,120.14 67.82,119.63 A19.F2 | A18.L2 80.52,105.66 80.52,100.58 A18.N2 | A18.U2 83.82,84.84 83.82,88.65 82.8,89.66 82.8,90.93 80.77,92.96 A18.R2 | 83.57,124.97 83.57,123.7 81.15,121.28 | 83.57,124.97 83.57,128.02 A18.C2 | 81.15,121.28 80.01,120.14 80.52,119.63 A18.F2 | 70.87,123.7 78.74,123.7 81.15,121.28 | 55.12,111.25 55.12,106.93 A20.L2 | 55.12,111.25 55.12,112.01 A20.J2 55.12,113.28 55.12,118.36 A20.F2 | A21.N2 42.42,99.31 42.42,94.23 A21.R2 43.18,92.96 44.7,91.44 44.7,89.66 45.72,88.65 45.72,84.84 A21.U2 | A21.J2 42.42,112.01 42.42,106.93 A21.L2 | A21.J2 42.42,113.28 42.42,118.36 A21.F2 42.16,119.38 38.35,119.38 32.77,124.97 | A23.N2 17.02,99.31 17.02,94.23 A23.R2 17.78,92.96 19.3,91.44 19.3,89.66 20.19,88.77
  Bottom 0.381: 20.19,88.77 20.32,88.65 20.32,84.84 A23.U2 | A23.J2 17.02,112.01 17.02,106.93 A23.L2 | 32.64,89.03 32,89.66 32,91.44 30.48,92.96 A22.R2 | 32.64,89.03 33.02,88.65 33.02,84.84 A22.U2 | A22.J2 29.72,112.01 29.72,106.93 A22.L2 | 32.77,124.97 32.77,123.7 29.21,120.14 29.72,119.63 A22.F2 | 32.77,124.97 32.77,128.02 A22.C2 | 20.19,88.77 20.32,88.9 32.51,88.9 32.64,89.03 | 55.12,111.25 44.45,111.25 43.43,112.27 A21.J2 | 70.87,127.25 60.45,127.25 59.44,128.27 A20.C2 | v215.9,122.17 215.39,122.17 212.85,124.71 212.85,126.75 211.58,128.02 A08.C2
I_3CYCLE  (via drill 0.61)
  Top 0.305: v259.84,60.45 259.84,60.96 260.1,61.21 260.1,65.79 v260.35,66.04 | v244.35,80.77 244.35,82.04 245.62,83.31 245.62,85.34 246.13,85.85 246.63,85.85 v252.73,91.95 | v72.9,28.19 v72.9,44.45
  2 0.305: v259.84,60.45 254.76,55.37 254.76,53.59 253.75,52.58 253.75,48.51 247.65,42.42 248.92,41.15 248.92,40.39 B05.K2 | v250.7,102.11 250.7,106.68 251.71,107.7 252.22,107.7 252.98,108.46 252.98,109.47 251.21,111.25 249.94,109.98 A05.K2 | v152.4,8.38 158.75,8.38 172.47,22.1 176.53,22.1 193.55,39.12 193.55,44.7 195.83,46.99 195.83,47.5 197.61,49.28 199.64,49.28 200.91,50.55 205.99,50.55 v216.66,61.21
  15 0.305: v252.73,91.95 255.52,94.74 250.95,99.31 250.95,101.85 v250.7,102.11 | v238.76,41.4 239.27,41.4 242.32,38.35 247.9,38.35 B05.K2
  Bottom 0.305: v260.35,66.04 260.35,67.06 248.41,78.99 246.13,78.99 v244.35,80.77 | v72.9,44.45 72.9,46.48 70.61,48.77 68.83,48.77 B19.F2 | v72.9,28.19 95,6.1 99.06,6.1 102.87,2.29 146.3,2.29 v152.4,8.38 | v216.66,61.21 218.19,61.21 226.06,53.34 226.82,53.34 v238.76,41.4
I_AC00  (via drill 0.61)
  Top 0.305: v93.73,66.55 93.98,66.55 120.4,92.96 120.4,97.03 143.76,120.4 144.53,120.4 v146.05,121.92 | v241.05,109.47 241.05,110.24 242.06,111.25 242.06,111.76 249.68,119.38 250.7,119.38 267.72,136.4 271.27,136.4 276.35,131.32 277.11,132.08 A03.B1
  2 0.305: v146.05,121.92 147.83,120.14 155.96,128.27 156.97,128.27 159.51,130.81 160.53,130.81 162.81,133.1 180.09,133.1 181.61,134.62 183.39,134.62 v184.15,135.38 | B03.B1 277.37,61.21 277.37,58.17 276.86,57.66 275.59,57.66 275.34,57.4 274.07,57.4 269.24,62.23 269.75,62.74 269.75,63.5 270.51,64.26 270.51,69.09 277.88,76.45 277.88,77.22 282.96,82.3 282.96,84.07 285.5,86.61 285.5,91.19 285.75,91.44 285.75,92.2 286.26,92.71 286.26,93.73 288.8,96.27 288.8,102.62 295.15,108.97 295.15,113.28 299.72,117.86 299.72,118.62 300.48,119.38 300.48,120.65 301.5,121.67 301.5,122.94 290.07,134.37 288.54,132.84 287.27,132.84 284.73,130.3 279.4,130.3 278.38,131.32 A03.B1
  15 0.305: v184.15,135.38 188.98,140.21 189.99,140.21 190.25,139.95 192.79,139.95 195.33,137.41 204.22,137.41 215.65,125.98 219.2,125.98 220.98,127.76 238.76,109.98 239.01,109.98 239.52,109.47 v241.05,109.47
  Bottom 0.305: v93.73,66.55 95.25,65.02 95.25,64.77 104.14,55.88 105.66,55.88 B16.D2
I_AC01  (via drill 0.61)
  Top 0.305: v97.03,60.45 97.03,60.96 118.36,82.3 122.43,82.3 171.2,131.06 173.48,131.06 178.82,136.4 180.09,136.4 v184.66,140.97
  2 0.305: v226.82,123.7 228.6,123.7 232.41,127.51 233.43,127.51 235.97,130.05 240.03,130.05 244.35,134.37 247.9,134.37 250.44,131.83 251.71,133.1 272.03,133.1 278.38,126.75 277.62,125.98 A03.D1 | v306.07,95.25 304.55,93.73 304.55,92.96 300.74,89.15 300.74,86.87 283.72,69.85 283.72,64.77 278.38,59.44 278.38,56.13 B03.D1
  15 0.305: v184.66,140.97 186.44,142.75 198.37,142.75 200.91,140.21 203.96,140.21 210.57,133.6 214.63,133.6 v217.17,131.06 | v306.07,95.25 305.05,96.27 305.05,106.43 300.48,111 290.32,111 279.65,121.67 279.65,123.19 278.13,124.71 A03.D1
  Bottom 0.305: v97.03,60.45 105.92,51.56 105.92,49.78 B16.F2 | v217.17,131.06 219.46,131.06 v226.82,123.7
I_AC02  (via drill 0.61)
  Top 0.305: v136.4,74.93 120.65,59.18 119.63,59.18 106.93,46.48 106.93,43.43 B16.J2 | v148.08,67.56 161.29,67.56 v161.8,68.07 | v238,32.26 240.54,34.8 246.89,34.8 v256.03,43.94 | v260.35,39.62 260.35,40.13 261.37,41.15 267.72,41.15 277.11,50.55 279.15,50.55 B03.E1 | v302.51,103.63 306.83,99.31 305.05,97.54 305.05,89.41 v304.8,89.15
  2 0.305: v172.97,55.37 173.99,55.37 186.44,67.82 186.44,69.6 v187.71,70.87 | v304.8,89.15 304.8,84.58 301.75,81.53 301.75,80.52 299.97,78.74 299.97,74.68 289.31,64.01 289.31,63.5 284.73,58.93 284.73,58.17 282.7,56.13 282.7,54.36 281.43,53.09 B03.E1
  15 0.305: v187.71,70.87 190.75,70.87 204.22,57.4 210.31,57.4 222.76,44.96 222.76,43.94 226.57,40.13 228.6,40.13 230.12,41.66 238,33.78 v238,32.26 | v256.03,43.94 256.03,43.69 260.1,39.62 v260.35,39.62
  Bottom 0.305: v136.4,74.93 140.72,74.93 v148.08,67.56 | v161.8,68.07 161.8,67.56 169.67,59.69 169.67,58.67 v172.97,55.37 | v302.51,103.63 294.89,111.25 290.07,111.25 281.43,119.89 281.43,121.67 A03.E1
I_AC03  (via drill 0.61)
  Top 0.305: v249.68,4.57 279.65,34.54 279.65,40.39 280.42,41.15 280.42,45.47 B03.H1 | v208.28,27.94 205.99,30.23 203.71,27.94 201.42,27.94 183.13,9.65 177.8,9.65 169.67,1.52 165.61,1.52 v165.35,1.27
  2 0.305: v114.81,30.48 116.33,30.48 132.33,46.48 132.84,46.48 139.19,52.83 139.19,54.61 152.15,67.56 152.65,67.56 172.97,87.88 174.75,87.88 175.51,88.65 181.86,88.65 185.17,91.95 189.23,91.95 202.95,105.66 202.95,106.17 203.45,106.68 203.96,106.68 225.3,128.02 225.3,128.52 226.31,129.54 227.84,129.54 230.89,132.59 232.16,132.59 235.97,136.4 237.74,136.4 239.52,138.18 244.09,138.18 245.36,139.45 250.7,139.45 250.95,139.7 v254.25,139.7
  15 0.305: v249.68,4.57 240.28,4.57 239.78,5.08 231.14,5.08 v208.28,27.94 | v165.35,1.27 145.03,1.27 141.99,4.32 141.48,4.32 115.06,30.73 v114.81,30.48
  Bottom 0.305: v114.81,30.48 109.22,36.07 106.93,36.07 B16.L2 | v254.25,139.7 255.27,139.7 277.37,117.6 279.15,117.6 280.42,116.33 A03.H1
I_AC04  (via drill 0.61)
  Top 0.305: v189.99,32 192.79,32 201.17,40.39 v201.17,40.64 | v228.6,31.5 233.17,31.5 234.44,32.77 234.44,33.27 242.32,41.15 242.82,41.15 v243.08,41.4 | v250.7,35.31 251.97,34.04 260.1,42.16 v260.1,45.72 259.84,45.97 261.62,47.75 272.03,47.75 278.13,53.85 v279.65,53.85 | v271.27,34.8 271.78,34.8 276.1,39.12 276.1,40.89 277.37,42.16 B03.J1 | v280.92,70.1 v278.13,67.31
  2 0.305: v138.18,53.34 116.33,31.5 112.01,31.5 111.25,30.73 106.93,30.73 B16.N2 | v254.76,91.95 256.54,93.73 256.54,94.74 274.07,112.27 277.11,112.27 A03.J1 | v287.53,63.25 287.53,62.74 283.97,59.18 283.97,58.42 279.65,54.1 v279.65,53.85
  Bottom 0.305: v138.18,53.34 140.21,55.37 155.45,40.13 155.45,36.32 159.77,32 165.61,32 167.13,30.48 167.64,30.48 169.42,28.7 177.8,28.7 183.13,34.04 185.17,32 v189.99,32 | v201.17,40.64 201.93,40.64 210.57,32 228.09,32 v228.6,31.5 | v243.08,41.4 244.6,41.4 v250.7,35.31 | v260.1,45.72 260.35,45.72 v271.27,34.8 | v254.76,91.95 253.24,90.42 276.35,67.31 v278.13,67.31 | v280.92,70.1 283.72,67.31 283.72,66.8 287.27,63.25 v287.53,63.25
I_AC05  (via drill 0.61)
  Top 0.305: v99.57,21.34 101.6,23.37 105.66,23.37 B16.R2 | v141.22,6.1 143.76,6.1 v154.43,16.76 | v175.51,33.78 176.78,33.78 178.56,35.56 179.58,35.56 181.86,37.85 188.21,37.85 194.56,44.2 199.64,44.2 202.44,46.99 203.71,46.99 207.26,50.55 211.33,50.55 219.2,58.42 v219.2,58.67 219.46,58.67 227.33,66.55 v227.33,67.06 | v264.41,25.65 264.92,25.65 274.07,34.8 275.84,34.8 277.11,36.07 B03.L1
  2 0.305: v154.43,16.76 166.12,28.45 170.18,28.45 v175.51,33.78 | v227.33,67.06 230.12,69.85 231.14,69.85 231.39,70.1 233.43,70.1 234.95,71.63 235.46,71.63 238.76,74.93 240.28,74.93 244.86,79.5 246.38,79.5 246.63,79.76 247.14,79.76 249.43,82.04 250.19,82.04 250.95,82.8 256.29,82.8 266.95,93.47 266.95,97.54 275.34,105.92 277.11,105.92 A03.L1
  Bottom 0.305: v99.57,21.34 100.58,21.34 108.97,12.95 114.3,12.95 115.06,12.19 116.08,12.19 118.62,9.65 123.95,9.65 124.71,8.89 130.05,8.89 130.81,8.13 132.33,8.13 133.6,6.86 140.46,6.86 v141.22,6.1 | v219.2,58.67 219.71,58.67 238,40.39 240.03,40.39 248.41,32 249.68,32 250.19,31.5 254.51,31.5 258.06,27.94 259.08,27.94 261.37,25.65 v264.41,25.65
I_AC06  (via drill 0.61)
  Top 0.305: v229.36,8.38 227.33,8.38 v221.23,2.29 | v275.59,98.55 276.35,99.31 276.35,100.58 278.38,102.62 280.42,102.62 A03.M1
  2 0.305: v256.79,1.78 264.67,9.65 265.68,9.65 282.96,26.92 281.43,28.45 281.43,32.77 B03.M1 | v119.63,73.66 119.63,73.15 110.24,63.75 103.89,63.75 97.54,57.4 95.5,57.4 B17.D2
  15 0.305: v221.23,2.29 219.46,4.06 217.93,4.06 214.88,7.11 213.87,7.11 211.58,9.4 207.77,9.4 199.39,17.78 196.85,17.78 195.83,18.8 189.48,18.8 186.18,22.1 182.37,22.1 174.5,29.97 v174.5,30.23 | v263.14,104.9 257.56,104.9 252.48,109.98 250.7,109.98 240.28,120.4 236.47,120.4 222.76,134.11 220.98,134.11 218.44,131.57 214.38,135.64 212.34,135.64 211.58,136.4 208.79,136.4 204.22,140.97 201.17,140.97 198.63,143.51 170.43,143.51 169.16,142.24 152.91,142.24 152.65,142.49 127.76,142.49 103.12,117.86 107.7,113.28 107.7,95.25 112.01,90.93 112.01,89.92 114.05,87.88 114.05,79.25 v119.63,73.66
  Bottom 0.305: v256.79,1.78 250.19,1.78 249.43,2.54 247.4,2.54 246.89,3.05 246.38,3.05 245.62,3.81 242.06,3.81 239.52,6.35 239.52,6.86 239.01,7.37 232.92,7.37 231.9,8.38 v229.36,8.38 | v174.5,30.23 171.7,30.23 157.73,44.2 153.92,44.2 131.32,66.8 126.49,66.8 v119.63,73.66 | v275.59,98.55 269.49,98.55 v263.14,104.9
I_AC07  (via drill 0.61)
  Top 0.305: v283.97,28.45 282.96,27.43 281.69,27.43 B03.P1 | v295.4,51.31 295.4,52.07 306.32,62.99 v306.32,63.25 | v210.82,2.54 214.12,2.54 222,10.41 222,10.67 v222.76,11.43
  2 0.305: v283.97,28.45 290.83,28.45 295.15,32.77 295.15,37.85 v299.97,42.67 | v246.38,2.03 247.9,2.03 248.41,2.54 255.27,2.54 258.57,5.84 258.57,8.38 272.8,22.61 274.57,22.61 277.11,25.15 279.15,25.15 B03.P1
  15 0.305: v306.32,63.25 305.05,64.52 305.05,68.83 303.78,70.1 303.78,71.12 302.01,72.9 302.01,73.41 297.94,77.47 297.94,77.98 295.4,80.52 295.4,84.33 284.73,95 283.21,95 281.69,96.52 A03.P1 | v167.13,8.64 178.82,8.64 180.59,6.86 188.47,6.86 190.75,4.57 192.28,4.57 193.8,3.05 196.85,3.05 198.63,1.27 205.49,1.27 208.03,3.81 209.55,3.81 v210.82,2.54
  Bottom 0.305: v299.97,42.67 299.97,44.2 295.4,48.77 v295.4,51.31 | v167.13,8.64 166.12,9.65 163.07,9.65 140.97,31.75 119.63,31.75 119.38,32 115.32,32 103.89,43.43 102.87,43.43 97.54,48.77 94.23,48.77 B17.F2 | v222.76,11.43 223.77,11.43 229.62,5.59 237.74,5.59 238,5.33 239.52,5.33 241.81,3.05 245.36,3.05 v246.38,2.03
I_AC08  (via drill 0.61)
  Top 0.305: v116.84,24.13 117.35,24.13 128.02,34.8 v131.06,34.8 | v276.61,88.39 278.13,89.92 280.42,89.92 A03.S1
  2 0.305: v194.31,4.06 200.15,4.06 200.66,4.57 205.74,4.57 206.25,5.08 210.57,5.08 210.82,5.33 212.09,5.33 216.92,10.16 217.68,10.16 219.96,12.45 228.09,12.45 230.38,10.16 235.97,15.75 240.03,15.75 241.05,16.76 241.05,17.53 v242.57,19.05 | v276.61,88.39 276.61,87.88 276.35,87.63 276.35,86.61 278.38,84.58 278.38,83.57 276.35,81.53 276.35,79.5 275.84,78.99 274.57,78.99 273.05,77.47 273.05,76.2 265.18,68.33 265.18,66.8 263.91,65.53 263.91,62.48 263.65,62.23 263.65,61.21 271.78,53.09 v269.49,50.8
  15 0.305: v131.06,34.8 131.57,34.8 147.07,19.3 157.99,19.3 162.81,14.48 164.59,14.48 169.42,9.65 178.82,9.65 180.85,7.62 188.72,7.62 191.01,5.33 193.04,5.33 v194.31,4.06 | v242.57,19.05 246.38,19.05 259.59,5.84 267.21,5.84 271.02,9.65 270,10.67 270,11.68 279.91,21.59 | 279.91,21.59 280.42,21.08 B03.S1 | v269.49,50.8 269.49,50.29 270,49.78 270,48.77 274.07,44.7 274.07,42.16 279.15,37.08 279.15,22.35 279.91,21.59
  Bottom 0.305: v116.84,24.13 102.62,38.35 96.27,38.35 93.98,40.64 93.98,42.16 B17.J2
I_AC09  (via drill 0.61)
  Top 0.305: v204.47,71.63 211.84,78.99 211.84,80.52 v220.73,89.41
  2 0.305: v115.57,22.35 120.14,22.35 173.48,75.69 176.78,75.69 v179.58,78.49 | v193.29,66.8 196.6,66.8 197.61,67.82 200.66,67.82 v204.47,71.63 | v269.24,105.92 268.99,105.92 257.3,94.23 257.3,90.17 249.94,82.8 248.67,82.8 v247.9,82.04
  15 0.305: v220.73,89.41 220.98,89.66 224.79,85.85 225.3,85.85 229.11,82.04 229.11,81.79 229.62,81.28 231.14,81.28 232.92,79.5 243.33,79.5 245.87,76.96 248.41,76.96 248.92,76.45 | 248.92,76.45 257.81,67.56 257.81,67.06 261.11,63.75 263.65,63.75 264.16,63.25 265.68,63.25 269.75,59.18 269.75,57.4 271.02,56.13 B03.D2 | v269.24,105.92 262.13,113.03 271.02,121.92 271.02,124.71 A03.D2 | v247.9,82.04 247.9,79.5 248.92,78.49 248.92,76.45
  Bottom 0.305: v115.57,22.35 112.27,22.35 109.73,24.89 108.71,24.89 97.54,36.07 94.23,36.07 B17.L2 | v179.58,78.49 180.09,78.49 181.86,76.71 183.39,76.71 v193.29,66.8
I_AC10  (via drill 0.61)
  Top 0.305: v148.34,87.88 148.34,88.14 v199.9,139.7
  2 0.305: v148.34,87.88 137.41,76.96 137.41,74.42 131.83,68.83 131.83,65.28 97.28,30.73 94.23,30.73 B17.N2 | A03.E2 275.08,122.94 276.35,124.21 276.35,125.48 275.08,126.75 264.41,126.75 262.38,124.71 261.37,124.71 250.7,114.05 245.36,114.05 244.09,112.78 241.55,115.32 240.28,115.32 237.74,112.78 238.51,112.01 238.51,107.19 237.24,105.92 v235.2,105.92 235.2,105.66 233.68,104.14 247.4,90.42 247.4,86.61 246.63,85.85 v246.63,84.84
  15 0.305: v246.63,84.84 264.92,66.55 268.73,66.55 273.3,61.98 273.3,58.17 274.32,57.15 274.32,53.09 B03.E2
  Bottom 0.305: v199.9,139.7 201.93,139.7 229.62,112.01 229.62,111.51 230.12,111 230.63,111 234.7,106.93 234.7,106.43 v235.2,105.92
I_AC11  (via drill 0.61)
  2 0.305: v208.03,139.7 206.25,137.92 206.25,134.37 195.58,123.7 191.52,123.7 177.55,109.73 177.55,105.66 158.75,86.87 158.75,85.09 158.5,84.84 158.5,80.26 157.99,79.76 157.73,79.76 152.15,74.17 152.15,73.91 113.03,34.8 108.97,34.8 98.55,24.38 94.23,24.38 B17.R2 | v219.96,134.62 220.73,133.86 223.27,136.4 232.66,136.4 235.2,138.94 238.25,138.94 239.01,139.7 243.33,139.7 v246.13,142.49 | v301.5,82.8 284.48,65.79 284.48,64.52 279.15,59.18 279.15,54.86 275.08,50.8 275.08,46.74 B03.H2
  15 0.305: v208.03,139.7 213.61,139.7 213.87,139.45 215.14,139.45 v219.96,134.62
  Bottom 0.305: v246.13,142.49 249.94,142.49 272.8,119.63 272.8,118.11 274.32,116.59 A03.H2 275.08,115.32 276.35,114.05 276.35,112.27 288.29,100.33 288.29,99.31 290.32,97.28 290.32,95.76 298.7,87.38 298.7,86.87 299.97,85.6 300.48,85.6 301.5,84.58 v301.5,82.8
I_ACCEPT  (via drill 0.61)
  Top 0.305: v240.54,6.86 245.11,6.86 250.19,11.94 251.21,11.94 258.06,18.8 260.1,18.8 B04.S2 261.37,20.83 260.6,20.07 257.05,23.62 v257.05,26.16 | v176.02,1.27 179.83,5.08 186.94,5.08 v193.29,11.43 | v207.01,1.27 207.01,1.78 222,16.76 222,18.8 B07.S2
  2 0.305: v269.24,80.26 269.24,78.49 267.72,76.96 266.95,76.96 263.91,73.91 263.91,73.15 259.59,68.83 259.59,66.8 259.33,66.55 259.33,64.52 268.73,55.12 266.95,53.34 266.95,46.74 263.65,43.43 263.65,37.08 257.3,30.73 257.3,26.42 v257.05,26.16
  Bottom 0.305: v240.54,6.86 230.38,17.02 228.85,17.02 228.35,17.53 228.35,18.03 226.06,20.32 224.54,20.32 B07.S2 | v176.02,1.27 138.94,38.35 134.37,38.35 132.08,40.64 131.06,40.64 125.98,45.72 122.94,45.72 B15.H2 | v193.29,11.43 195.07,13.21 v207.01,1.27 | v269.24,80.26 262.38,87.12 262.38,89.92 A04.S2
I_ACCLR  (via drill 0.61)
  Top 0.305: v181.1,39.88 181.86,39.88 v186.69,44.7 | v257.56,6.35 258.83,6.35 260.6,4.57 261.62,4.57 284.99,27.94 284.99,28.96 288.8,32.77 v288.8,34.8
  2 0.305: v304.8,59.94 304.55,59.94 301.75,57.15 301.75,55.12 301.5,54.86 301.5,51.82 295.15,45.47 295.15,39.12 290.83,34.8 v288.8,34.8 280.42,34.8 275.08,29.46 275.08,27.69 B03.P2 | v111,19.3 124.21,19.3 124.46,19.56 125.48,19.56 128.02,22.1 132.08,22.1 v158.75,48.77
  15 0.305: v186.69,44.7 189.48,44.7 195.83,38.35 204.22,38.35 226.57,16 231.9,16 239.01,8.89 241.05,8.89 241.3,8.64 v248.41,8.64
  Bottom 0.305: v304.8,59.94 304.8,62.23 304.55,62.48 304.55,65.02 276.35,93.22 276.35,95 275.08,96.27 A03.P2 | v111,19.3 108.97,19.3 106.68,21.59 105.66,21.59 101.6,25.65 96.27,25.65 81.28,40.64 81.28,42.16 B18.J2 | v158.75,48.77 162.05,48.77 163.07,47.75 173.23,47.75 v181.1,39.88 | v248.41,8.64 255.27,8.64 v257.56,6.35
I_ADD00  (via drill 0.61)
  Top 0.305: v87.63,26.92 90.68,23.88 121.41,54.61 122.43,54.61 124.71,56.9 129.03,56.9 v155.19,83.06 | v157.73,85.6 158.75,85.6 183.64,110.49 184.66,110.49 210.57,136.4 222,136.4 v225.55,139.95
  2 0.305: v157.73,85.6 v155.19,83.06 | v245.87,122.43 247.4,122.43 248.67,123.7 255.02,123.7 261.37,130.05 263.14,130.05 264.41,131.32 A04.B1 | v278.64,47.75 278.13,47.75 276.1,45.72 276.1,44.2 274.32,42.42 274.32,41.4 266.95,34.04 266.95,23.62 259.33,16 255.27,16 250.95,11.68 250.95,11.18 v250.7,10.92
  15 0.305: v278.64,47.75 277.37,47.75 265.43,59.69 265.43,61.21 B04.B1 | v227.58,26.16 207.01,46.74 205.99,46.74 186.18,66.55 184.15,66.55 182.12,68.58 v180.59,68.58
  Bottom 0.305: v87.63,26.92 59.44,55.12 56.13,55.12 B20.D2 | v225.55,139.95 225.55,137.67 232.92,130.3 238,130.3 v245.87,122.43 | v250.7,10.92 248.16,10.92 243.33,15.75 238,15.75 v227.58,26.16 | v180.59,68.58 179.83,68.58 163.07,85.34 162.05,85.34 161.04,86.36 158.5,86.36 v157.73,85.6
I_ADD01  (via drill 0.61)
  Top 0.305: v65.79,41.91 65.79,42.42 86.61,63.25 91.44,63.25 93.73,65.53 94.23,65.53 130.81,102.11 131.83,102.11 134.37,104.65 139.19,104.65 v157.99,123.44 | v261.11,125.98 264.67,125.98 A04.D1 | v238.76,76.96 238.76,74.93 235.97,72.14 230.89,72.14 v230.12,71.37 | v201.68,88.9 198.63,88.9 v197.61,87.88
  2 0.305: v180.59,104.9 180.59,107.44 183.64,110.49 184.4,110.49 188.47,114.55 188.47,115.32 212.85,139.7 217.17,139.7 v220.47,143
  15 0.305: v238.76,76.96 240.28,76.96 249.94,67.31 252.98,67.31 254.25,66.04 254.25,64.52 262.89,55.88 264.41,55.88 B04.D1 | v230.12,71.37 230.12,72.9 229.11,73.91 227.08,73.91 226.57,74.42 220.22,74.42 219.96,74.68 218.19,74.68 211.58,81.28 210.57,81.28 208.79,83.06 207.77,83.06 201.93,88.9 v201.68,88.9 | v180.59,104.9 v197.61,87.88
  Bottom 0.305: v65.79,41.91 58.93,48.77 56.13,48.77 B20.F2 | v157.99,123.44 160.78,126.24 169.42,117.6 169.42,116.08 v180.59,104.9 | v220.47,143 233.68,143 234.44,142.24 237.49,142.24 238,141.73 239.01,141.73 239.52,142.24 239.52,142.75 240.28,143.51 243.59,143.51 259.59,127.51 259.84,127.51 261.11,126.24 v261.11,125.98
I_ADD02  (via drill 0.61)
  Top 0.305: v95,7.62 111.51,7.62 122.94,19.05 123.44,19.05 130.56,26.16 131.06,26.16 156.21,51.31 157.23,51.31 169.16,63.25 171.45,63.25 171.7,63.5 173.74,63.5 189.23,78.99 190.5,78.99 v190.75,79.25 | v231.9,60.96 231.9,62.48 232.66,63.25 239.01,63.25 242.32,66.55 243.08,66.55 v245.36,68.83 | v233.17,141.48 232.66,141.48 v224.79,133.6 | v210.57,101.6 210.57,100.58 209.3,99.31 209.3,91.95 v205.49,88.14
  2 0.305: v190.75,79.25 190.75,79.76 191.52,80.52 192.79,80.52 197.87,85.6 202.95,85.6 v205.49,88.14 | v247.14,141.48 247.14,143 246.63,143.51 240.28,143.51 239.52,142.75 239.52,142.24 239.01,141.73 233.43,141.73 v233.17,141.48 | v224.79,133.6 221.49,133.6 220.98,133.1 218.69,133.1 218.44,132.84 217.42,132.84 v198.88,114.3
  15 0.305: v245.36,68.83 246.38,69.85 252.22,64.01 253.75,64.01 262.64,55.12 263.65,55.12 264.67,54.1 266.45,54.1 267.72,52.83 B04.E1
  Bottom 0.305: v95,7.62 60.2,42.42 56.13,42.42 B20.J2 | v205.49,88.14 205.49,87.88 219.46,73.91 219.71,73.91 220.22,73.41 220.22,72.64 v231.9,60.96 | v247.14,141.48 265.94,122.68 267.72,122.68 A04.E1 | v198.88,114.3 198.88,113.28 v210.57,101.6
I_ADD03  (via drill 0.61)
  Top 0.305: v135.38,119.89 135.38,119.63 89.66,73.91 89.66,72.39 89.15,71.88 88.9,71.88 70.1,53.09 70.1,52.83 68.58,51.31 68.33,51.31 56.13,39.12 56.13,37.08 B20.L2 | v206.25,71.88 213.36,71.88 221.23,79.76 221.49,79.76 225.55,83.82 v225.55,84.07 | v276.1,110.74 277.62,109.22 v265.18,96.77 | v271.27,90.68 271.27,90.17 262.13,81.03 262.13,80.01 246.63,64.52 v246.63,64.26
  15 0.305: v246.63,64.26 251.97,58.93 253.49,58.93 264.67,47.75 266.45,47.75 267.72,46.48 B04.H1
  Bottom 0.305: v135.38,119.89 133.35,119.89 129.29,123.95 129.29,124.46 128.78,124.97 128.78,125.48 135.64,132.33 137.67,130.3 147.83,130.3 161.8,116.33 161.8,112.52 185.17,89.15 188.98,89.15 v206.25,71.88 | v225.55,84.07 226.82,84.07 v246.63,64.26 | v276.1,110.74 271.27,115.57 268.99,115.57 A04.H1 | v271.27,90.68 v265.18,96.77
I_ADD04  (via drill 0.61)
  Top 0.305: v72.64,22.35 80.52,22.35 85.34,17.53 121.67,53.85 127,53.85 130.81,57.66 131.83,57.66 v153.16,78.99 | v224.54,120.14 225.04,120.14 235.71,130.81 236.73,130.81 v239.27,133.35 | v239.78,67.82 239.01,67.82 238.25,67.06 236.47,67.06 v236.22,66.8 | v224.54,78.23 223.01,78.23 217.42,72.64 215.14,72.64 213.61,71.12 207.01,71.12 206.76,70.87 205.23,70.87 v202.95,68.58
  2 0.305: v161.8,73.91 163.32,73.91 164.08,74.68 170.94,74.68 174.5,78.23 177.8,78.23 v183.9,84.33 197.87,98.3 202.95,98.3 224.54,119.89 v224.54,120.14
  15 0.305: v239.78,67.82 241.55,66.04 241.55,64.52 249.17,56.9 252.98,56.9 264.67,45.21 264.67,43.43 B04.J1
  Bottom 0.305: v72.64,22.35 69.34,25.65 58.17,25.65 55.88,27.94 55.88,29.46 B20.N2 | v153.16,78.99 156.72,78.99 v161.8,73.91 | v239.27,133.35 242.57,133.35 261.37,114.55 262.89,114.55 264.41,113.03 A04.J1 | v236.22,66.8 224.79,78.23 v224.54,78.23 | v202.95,68.58 202.44,68.58 194.56,76.45 191.77,76.45 188.72,79.5 188.47,79.5 183.9,84.07 v183.9,84.33
I_ADD05  (via drill 0.61)
  Top 0.305: v219.2,18.8 219.2,19.3 222.76,22.86 222.76,23.62 v225.3,26.16 | v234.95,132.84 234.95,131.32 230.89,127.25 226.82,127.25 222.5,122.94 222.5,118.11 v199.9,95.5 | v195.07,85.6 195.07,82.8 193.8,81.53 193.8,79.76 v181.61,67.56 | v202.95,45.97 202.95,41.91 v202.69,41.66
  2 0.305: v172.21,2.03 173.74,2.03 173.99,2.29 181.61,2.29 181.86,2.54 182.88,2.54 183.39,3.05 190.5,3.05 191.26,3.81 192.53,3.81 193.8,5.08 199.9,5.08 210.57,15.75 216.15,15.75 v219.2,18.8 | v244.09,5.59 244.09,5.84 257.56,19.3 257.81,19.3 258.32,19.81 258.32,20.32 260.86,22.86 260.86,23.88 263.4,26.42 263.4,34.54 264.67,35.81 B04.L1
  15 0.305: v212.6,38.35 214.38,38.35 225.3,27.43 v225.3,26.16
